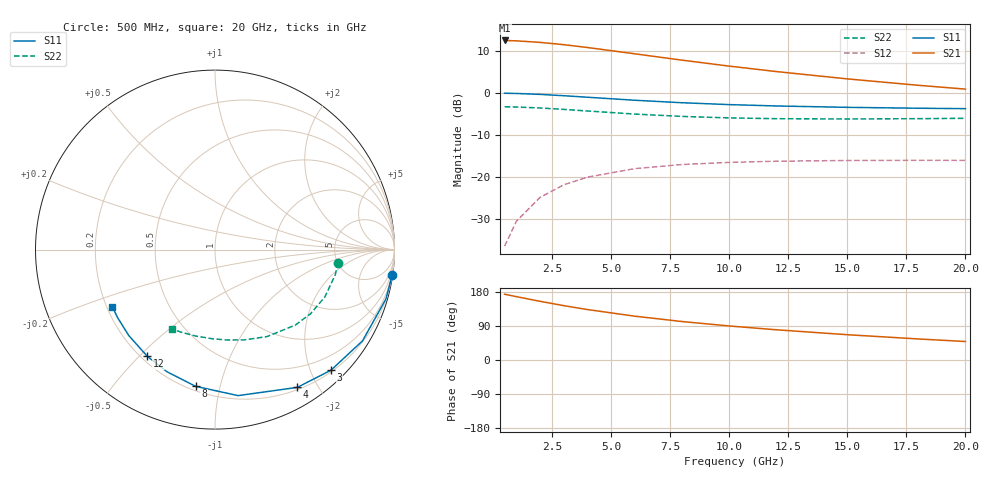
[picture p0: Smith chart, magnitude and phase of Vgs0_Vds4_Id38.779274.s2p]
# Hz S RI R 50
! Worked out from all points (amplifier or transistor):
!   12 points, 500 MHz to 20 GHz, reference 50 ohm
!   highest |S21| = 12.5 dB at 500 MHz (marker M1)
!   |S21| within 3 dB of that: start of sweep to 5.783 GHz
!   unconditionally stable (mu >= 1): 18.83 GHz to end of sweep
!   at 2 GHz: K = 0.10, MSG = 18.4 dB, |S12| = -24.8 dB
!   at 8 GHz: K = 0.40, MSG = 12.4 dB, |S12| = -17.0 dB
!   at 20 GHz: K = 1.07, MAG = 6.8 dB, |S12| = -16.0 dB
!   S11 on the Smith chart (normalised r, x): 500 MHz: 0, -14; 3 GHz: 0.23, -2.33; 4 GHz: 0.23, -1.74; 8 GHz: 0.23, -0.84; 12 GHz: 0.22, -0.53; 20 GHz: 0.22, -0.25
5e8  0.9877 -0.1411  -4.196 0.4743  0.00147 0.0152  0.6856 -0.072
1e9  0.9518 -0.2761  -4.072 0.9274  0.00574 0.0296  0.6697 -0.1414
2e9  0.8222 -0.508  -3.627 1.701  0.0211 0.0538  0.6121 -0.2638
3e9  0.6464 -0.6717  -3.025 2.239  0.0419 0.0698  0.5329 -0.357
4e9  0.4588 -0.7677  -2.385 2.541  0.0638 0.0776  0.447 -0.421
6e9  0.1288 -0.8135  -1.272 2.644  0.1016 0.0759  0.2891 -0.4847
8e9  -0.1084 -0.7617  -0.494 2.416  0.1273 0.0628  0.1645 -0.5031
1e10  -0.2684 -0.6799  0.00659 2.095  0.1431 0.0468  0.0675 -0.5036
1.2e10  -0.3769 -0.5949  0.3212 1.775  0.1522 0.0312  -0.0113 -0.4972
1.5e10  -0.4807 -0.4784  0.5828 1.357  0.1582 0.0104  -0.109 -0.4813
1.8e10  -0.5434 -0.3779  0.7013 1.022  0.1591 -0.00675  -0.1914 -0.4593
2e10  -0.5714 -0.3186  0.7354 0.8403  0.1582 -0.0165  -0.2402 -0.4413
